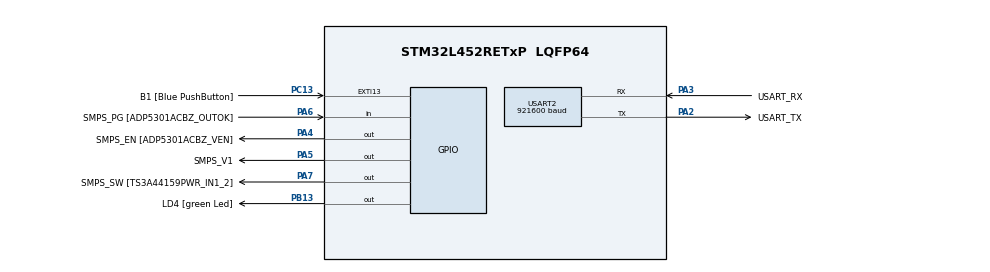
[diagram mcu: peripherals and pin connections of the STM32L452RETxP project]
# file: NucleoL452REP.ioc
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Dma.Request0=USART2_RX
Dma.USART2_RX.0.Direction=DMA_PERIPH_TO_MEMORY
Dma.USART2_RX.0.Instance=DMA1_Channel6
Dma.USART2_RX.0.MemDataAlignment=DMA_MDATAALIGN_BYTE
Dma.USART2_RX.0.MemInc=DMA_MINC_ENABLE
Dma.USART2_RX.0.Mode=DMA_NORMAL
Dma.USART2_RX.0.PeriphDataAlignment=DMA_PDATAALIGN_BYTE
Dma.USART2_RX.0.PeriphInc=DMA_PINC_DISABLE
Dma.USART2_RX.0.Priority=DMA_PRIORITY_MEDIUM
Mcu.Family=STM32L4
Mcu.Name=STM32L452RETxP
Mcu.Package=LQFP64
NVIC.DMA1_Channel6_IRQn=true\:0\:0\:false\:false\:true\:false\:true\:true
NVIC.PriorityGroup=NVIC_PRIORITYGROUP_4
NVIC.USART2_IRQn=true\:0\:0\:false\:false\:true\:true\:true\:true
PA13\ (JTMS/SWDIO).GPIO_Label=TMS
PA13\ (JTMS/SWDIO).Mode=Serial_Wire
PA13\ (JTMS/SWDIO).Signal=SYS_JTMS-SWDIO
PA14\ (JTCK/SWCLK).GPIO_Label=TCK
PA14\ (JTCK/SWCLK).Mode=Serial_Wire
PA14\ (JTCK/SWCLK).Signal=SYS_JTCK-SWCLK
PA2.GPIO_Label=USART_TX
PA2.GPIO_Mode=GPIO_MODE_AF_PP
PA2.GPIO_PuPd=GPIO_NOPULL
PA2.GPIO_Speed=GPIO_SPEED_FREQ_VERY_HIGH
PA2.Mode=Asynchronous
PA2.Signal=USART2_TX
PA3.GPIO_Label=USART_RX
PA3.GPIO_Mode=GPIO_MODE_AF_PP
PA3.GPIO_PuPd=GPIO_NOPULL
PA3.GPIO_Speed=GPIO_SPEED_FREQ_VERY_HIGH
PA3.Mode=Asynchronous
PA3.Signal=USART2_RX
PA4.GPIO_Label=SMPS_EN [ADP5301ACBZ_VEN]
PA4.Signal=GPIO_Output
PA5.GPIO_Label=SMPS_V1
PA5.GPIO_ModeDefaultOutputPP=GPIO_MODE_OUTPUT_PP
PA5.GPIO_PuPd=GPIO_NOPULL
PA5.GPIO_Speed=GPIO_SPEED_FREQ_LOW
PA5.Signal=GPIO_Output
PA6.GPIO_Label=SMPS_PG [ADP5301ACBZ_OUTOK]
PA6.GPIO_PuPd=GPIO_PULLUP
PA6.Signal=GPIO_Input
PA7.GPIO_Label=SMPS_SW [TS3A44159PWR_IN1_2]
PA7.Signal=GPIO_Output
PB13.GPIO_Label=LD4 [green Led]
PB13.Signal=GPIO_Output
PB3\ (JTDO/TRACESWO).GPIO_Label=SWO
PB3\ (JTDO/TRACESWO).Signal=SYS_JTDO-SWO
PC13.GPIO_Label=B1 [Blue PushButton]
PC13.GPIO_ModeDefaultEXTI=GPIO_MODE_IT_FALLING
PC13.GPIO_PuPd=GPIO_NOPULL
PC13.Signal=GPXTI13
PC14-OSC32_IN\ (PC14).Mode=LSE-External-Oscillator
PC14-OSC32_IN\ (PC14).Signal=RCC_OSC32_IN
PC15-OSC32_OUT\ (PC15).Mode=LSE-External-Oscillator
PC15-OSC32_OUT\ (PC15).Signal=RCC_OSC32_OUT
PH0-OSC_IN\ (PH0).GPIO_Label=MCO
PH0-OSC_IN\ (PH0).Mode=HSE-External-Clock-Source
PH0-OSC_IN\ (PH0).Signal=RCC_OSC_IN
PH1-OSC_OUT\ (PH1).Signal=RCC_OSC_OUT
ProjectManager.HeapSize=0x200
ProjectManager.StackSize=0x400
ProjectManager.TargetToolchain=Makefile
RCC.ADCFreq_Value=64000000
RCC.AHBFreq_Value=80000000
RCC.APB1Freq_Value=80000000
RCC.APB1TimFreq_Value=80000000
RCC.APB2Freq_Value=80000000
RCC.APB2TimFreq_Value=80000000
RCC.CortexFreq_Value=80000000
RCC.HCLKFreq_Value=80000000
RCC.HSE_VALUE=8000000
RCC.HSI48_VALUE=48000000
RCC.HSI_VALUE=16000000
RCC.MSI_VALUE=4000000
RCC.PLLN=10
RCC.PLLSourceVirtual=RCC_PLLSOURCE_HSI
RCC.PREFETCH_ENABLE=1
RCC.SYSCLKFreq_VALUE=80000000
RCC.SYSCLKSource=RCC_SYSCLKSOURCE_PLLCLK
RCC.USART2CLockSelection=RCC_USART2CLKSOURCE_SYSCLK
RCC.USBFreq_Value=64000000
RCC.VCOOutputFreq_Value=160000000
USART2.BaudRate=921600
USART2.VirtualMode-Asynchronous=VM_ASYNC
board=NUCLEO-L452RE-P

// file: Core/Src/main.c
/* USER CODE BEGIN Header */
/**
  ******************************************************************************
  * @file           : main.c
  * @brief          : Main program body
  ******************************************************************************
  * @attention
  *
  * Copyright (c) 2024 STMicroelectronics.
  * All rights reserved.
  *
  * This software is licensed under terms that can be found in the LICENSE file
  * in the root directory of this software component.
  * If no LICENSE file comes with this software, it is provided AS-IS.
  *
  ******************************************************************************
  */
/* USER CODE END Header */
#include "main.h"

/* USER CODE BEGIN Includes */
#include <stdint.h>
#include <stdio.h>

#include "NeuralNetwork.h"
/* USER CODE END Includes */

/* USER CODE BEGIN PD */
#define MAX_READ_SIZE 16384 // Absolute max is 65535 due to HAL_UART_Receive_DMA size being uint16_t
/* USER CODE END PD */

UART_HandleTypeDef huart2;
DMA_HandleTypeDef hdma_usart2_rx;

/* USER CODE BEGIN PV */
static char receive_buff[MAX_READ_SIZE] = {'\0'};                //Define the receive array
volatile uint16_t receive_buff_cnt = 0;
static char send_msg[32] = "READY\r\n";
/* USER CODE END PV */

void SystemClock_Config(void);
static void MX_GPIO_Init(void);
static void MX_DMA_Init(void);
static void MX_USART2_UART_Init(void);

/* USER CODE BEGIN 0 */
void RxEventCallback(UART_HandleTypeDef *huart, uint16_t Pos) {
  if(huart->Instance == USART2) { //Determine whether it is serial port 2
    uint16_t max_read = MAX_READ_SIZE - receive_buff_cnt;

    //Calculate the length of the received data
    //uint16_t data_length  = max_read - __HAL_DMA_GET_COUNTER(&hdma_usart2_rx);
    uint16_t data_length = Pos;

    receive_buff_cnt += data_length;

    if (receive_buff[receive_buff_cnt - 1] != '\n') {
      max_read -= data_length;
      //Restart to start DMA transmission of MAX_READ_SIZE bytes of data at a time
      HAL_UARTEx_ReceiveToIdle_DMA(&huart2, (uint8_t*)(receive_buff + receive_buff_cnt), max_read);
    }
  }
}

/**
  * @brief  Function called to read the current micro second
  * @param  None
  * @retval None
  */
uint32_t getCurrentMicros(void)
{
  uint32_t m0 = HAL_GetTick();
  __IO uint32_t u0 = SysTick->VAL;
  uint32_t m1 = HAL_GetTick();
  __IO uint32_t u1 = SysTick->VAL;
  const uint32_t tms = SysTick->LOAD + 1;

  if (m1 != m0) {
    return (m1 * 1000 + ((tms - u1) * 1000) / tms);
  } else {
    return (m0 * 1000 + ((tms - u0) * 1000) / tms);
  }
}
/* USER CODE END 0 */

int main(void)
{

  /* MCU Configuration--------------------------------------------------------*/

  /* Reset of all peripherals, Initializes the Flash interface and the Systick. */
  HAL_Init();

  /* Configure the system clock */
  SystemClock_Config();

  /* Initialize all configured peripherals */
  MX_GPIO_Init();
  MX_DMA_Init();
  MX_USART2_UART_Init();
  /* USER CODE BEGIN 2 */
  HAL_UART_RegisterRxEventCallback(&huart2, RxEventCallback);
  HAL_UARTEx_ReceiveToIdle_DMA(&huart2, (uint8_t*)receive_buff, MAX_READ_SIZE);
  HAL_UART_Transmit(&huart2, (unsigned char *)send_msg, 7, 0x200); // Send READY
  /* USER CODE END 2 */

  /* Infinite loop */
  /* USER CODE BEGIN WHILE */
  while (1)
  {
    if (receive_buff_cnt > 0 && receive_buff[receive_buff_cnt - 1] == '\n') {
      float *inputs = serialBufToFloats(receive_buff, receive_buff_cnt);
      size_t len = snprintf(send_msg, 32, "%d\r\n", receive_buff_cnt);
      receive_buff_cnt = 0;
      HAL_UARTEx_ReceiveToIdle_DMA(&huart2, (uint8_t*)receive_buff, MAX_READ_SIZE);

      HAL_UART_Transmit(&huart2, (unsigned char *)send_msg, len, 0x200);

      uint32_t start = getCurrentMicros();
      struct NNResult res = neuralNetworkInfer(inputs);
      uint32_t stop = getCurrentMicros();

      len = snprintf(send_msg, 32, "%d,%d,%f,%lu\r\n", res.inference_count, res.label, (double)res.dist, stop - start);
      HAL_UART_Transmit(&huart2, (unsigned char *)send_msg, len, 0x200);
    }
    /* USER CODE END WHILE */

  }
}

void SystemClock_Config(void)
{
  RCC_OscInitTypeDef RCC_OscInitStruct = {0};
  RCC_ClkInitTypeDef RCC_ClkInitStruct = {0};

  /** Configure the main internal regulator output voltage
  */
  if (HAL_PWREx_ControlVoltageScaling(PWR_REGULATOR_VOLTAGE_SCALE1) != HAL_OK)
  {
    Error_Handler();
  }

  /** Initializes the RCC Oscillators according to the specified parameters
  * in the RCC_OscInitTypeDef structure.
  */
  RCC_OscInitStruct.OscillatorType = RCC_OSCILLATORTYPE_HSI;
  RCC_OscInitStruct.HSIState = RCC_HSI_ON;
  RCC_OscInitStruct.HSICalibrationValue = 64;
  RCC_OscInitStruct.PLL.PLLState = RCC_PLL_ON;
  RCC_OscInitStruct.PLL.PLLSource = RCC_PLLSOURCE_HSI;
  RCC_OscInitStruct.PLL.PLLM = 1;
#ifdef CORE_CLOCK_48MHZ
  RCC_OscInitStruct.PLL.PLLN = 12;
#else
  RCC_OscInitStruct.PLL.PLLN = 10;
#endif
  RCC_OscInitStruct.PLL.PLLP = RCC_PLLP_DIV7;
  RCC_OscInitStruct.PLL.PLLQ = RCC_PLLQ_DIV2;
#ifdef CORE_CLOCK_48MHZ
  RCC_OscInitStruct.PLL.PLLR = RCC_PLLR_DIV4;
#else
  RCC_OscInitStruct.PLL.PLLR = RCC_PLLR_DIV2;
#endif
  if (HAL_RCC_OscConfig(&RCC_OscInitStruct) != HAL_OK)
  {
    Error_Handler();
  }

  /** Initializes the CPU, AHB and APB buses clocks
  */
  RCC_ClkInitStruct.ClockType = RCC_CLOCKTYPE_HCLK|RCC_CLOCKTYPE_SYSCLK
                              |RCC_CLOCKTYPE_PCLK1|RCC_CLOCKTYPE_PCLK2;
  RCC_ClkInitStruct.SYSCLKSource = RCC_SYSCLKSOURCE_PLLCLK;
  RCC_ClkInitStruct.AHBCLKDivider = RCC_SYSCLK_DIV1;
  RCC_ClkInitStruct.APB1CLKDivider = RCC_HCLK_DIV1;
  RCC_ClkInitStruct.APB2CLKDivider = RCC_HCLK_DIV1;

#ifdef CORE_CLOCK_48MHZ
  if (HAL_RCC_ClockConfig(&RCC_ClkInitStruct, FLASH_LATENCY_2) != HAL_OK)
#else
  if (HAL_RCC_ClockConfig(&RCC_ClkInitStruct, FLASH_LATENCY_4) != HAL_OK)
#endif
  {
    Error_Handler();
  }
}

static void MX_USART2_UART_Init(void)
{

  huart2.Instance = USART2;
  huart2.Init.BaudRate = 921600;
  huart2.Init.WordLength = UART_WORDLENGTH_8B;
  huart2.Init.StopBits = UART_STOPBITS_1;
  huart2.Init.Parity = UART_PARITY_NONE;
  huart2.Init.Mode = UART_MODE_TX_RX;
  huart2.Init.HwFlowCtl = UART_HWCONTROL_NONE;
  huart2.Init.OverSampling = UART_OVERSAMPLING_16;
  huart2.Init.OneBitSampling = UART_ONE_BIT_SAMPLE_DISABLE;
  huart2.AdvancedInit.AdvFeatureInit = UART_ADVFEATURE_NO_INIT;
  if (HAL_UART_Init(&huart2) != HAL_OK)
  {
    Error_Handler();
  }

}

static void MX_DMA_Init(void)
{

  /* DMA controller clock enable */
  __HAL_RCC_DMA1_CLK_ENABLE();

  /* DMA interrupt init */
  /* DMA1_Channel6_IRQn interrupt configuration */
  HAL_NVIC_SetPriority(DMA1_Channel6_IRQn, 0, 0);
  HAL_NVIC_EnableIRQ(DMA1_Channel6_IRQn);

}

static void MX_GPIO_Init(void)
{
  GPIO_InitTypeDef GPIO_InitStruct = {0};

  /* GPIO Ports Clock Enable */
  __HAL_RCC_GPIOC_CLK_ENABLE();
  __HAL_RCC_GPIOH_CLK_ENABLE();
  __HAL_RCC_GPIOA_CLK_ENABLE();
  __HAL_RCC_GPIOB_CLK_ENABLE();

  /*Configure GPIO pin Output Level */
  HAL_GPIO_WritePin(GPIOA, SMPS_EN_Pin|SMPS_V1_Pin|SMPS_SW_Pin, GPIO_PIN_RESET);

  /*Configure GPIO pin Output Level */
  HAL_GPIO_WritePin(LD4_GPIO_Port, LD4_Pin, GPIO_PIN_RESET);

  /*Configure GPIO pin : B1_Pin */
  GPIO_InitStruct.Pin = B1_Pin;
  GPIO_InitStruct.Mode = GPIO_MODE_IT_FALLING;
  GPIO_InitStruct.Pull = GPIO_NOPULL;
  HAL_GPIO_Init(B1_GPIO_Port, &GPIO_InitStruct);

  /*Configure GPIO pins : SMPS_EN_Pin SMPS_V1_Pin SMPS_SW_Pin */
  GPIO_InitStruct.Pin = SMPS_EN_Pin|SMPS_V1_Pin|SMPS_SW_Pin;
  GPIO_InitStruct.Mode = GPIO_MODE_OUTPUT_PP;
  GPIO_InitStruct.Pull = GPIO_NOPULL;
  GPIO_InitStruct.Speed = GPIO_SPEED_FREQ_LOW;
  HAL_GPIO_Init(GPIOA, &GPIO_InitStruct);

  /*Configure GPIO pin : SMPS_PG_Pin */
  GPIO_InitStruct.Pin = SMPS_PG_Pin;
  GPIO_InitStruct.Mode = GPIO_MODE_INPUT;
  GPIO_InitStruct.Pull = GPIO_PULLUP;
  HAL_GPIO_Init(SMPS_PG_GPIO_Port, &GPIO_InitStruct);

  /*Configure GPIO pin : LD4_Pin */
  GPIO_InitStruct.Pin = LD4_Pin;
  GPIO_InitStruct.Mode = GPIO_MODE_OUTPUT_PP;
  GPIO_InitStruct.Pull = GPIO_NOPULL;
  GPIO_InitStruct.Speed = GPIO_SPEED_FREQ_LOW;
  HAL_GPIO_Init(LD4_GPIO_Port, &GPIO_InitStruct);

}

void Error_Handler(void)
{
  __disable_irq();
  while (1)
  {
  }
}
